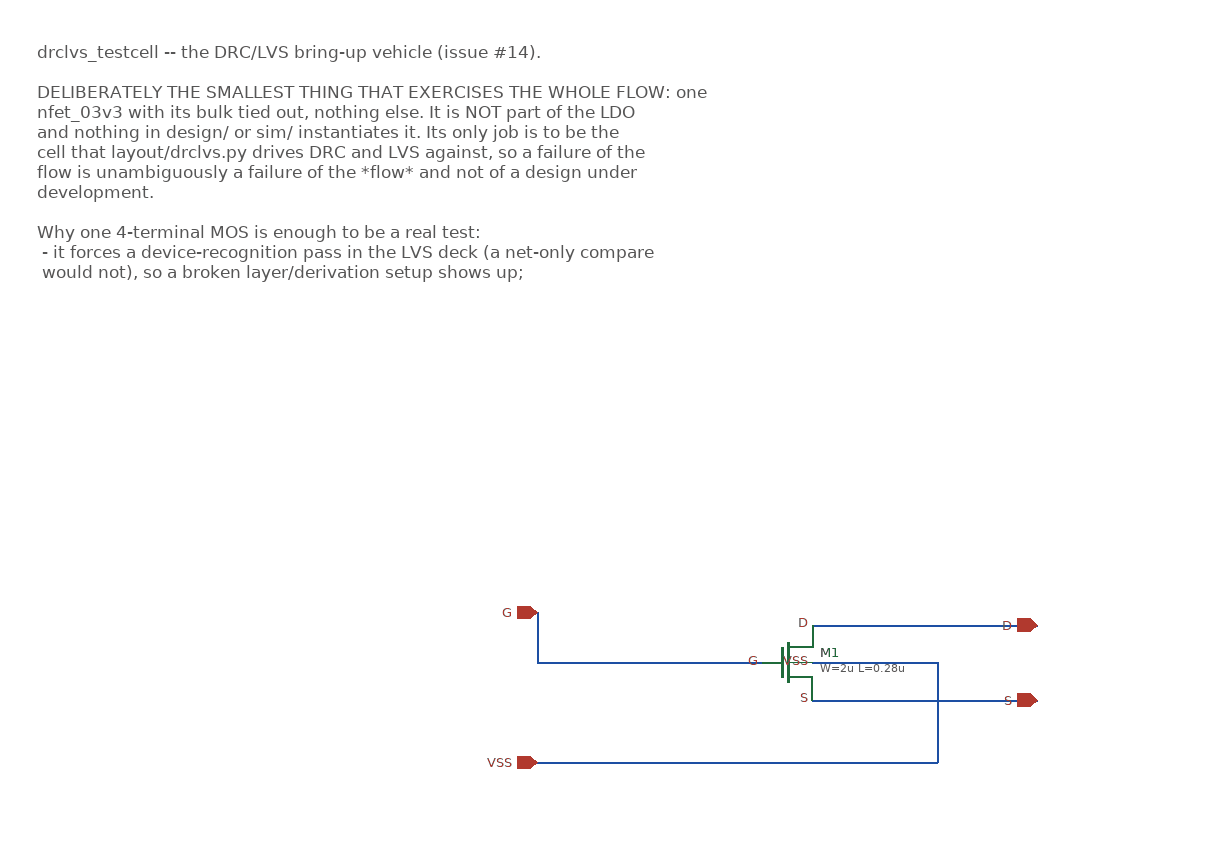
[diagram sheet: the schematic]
v {xschem version=3.4.7 file_version=1.2 }
G {}
K {}
V {}
S {}
E {}
T {drclvs_testcell -- the DRC/LVS bring-up vehicle (issue #14).

DELIBERATELY THE SMALLEST THING THAT EXERCISES THE WHOLE FLOW: one
nfet_03v3 with its bulk tied out, nothing else. It is NOT part of the LDO
and nothing in design/ or sim/ instantiates it. Its only job is to be the
cell that layout/drclvs.py drives DRC and LVS against, so a failure of the
flow is unambiguously a failure of the *flow* and not of a design under
development.

Why one 4-terminal MOS is enough to be a real test:
  - it forces a device-recognition pass in the LVS deck (a net-only compare
    would not), so a broken layer/derivation setup shows up;
  - W, L, nf and m all reach the extracted device, so a parameter-tolerance
    mismatch is detectable;
  - the bulk tie exercises the substrate/global-net path, which is where
    a top-level LVS most often goes wrong first.

PORTS (order is the .subckt port order -- taken from the ipin/opin/iopin
instance order below, since this cell has no symbol):

    D  G  S  VSS

VSS is the device bulk AND the substrate net the pinned LVS deck names itself
(rule_decks/substrate_connections.lvs hardcodes connect_global(..., 'SUB')),
so the guard-ring p-tap in the layout resolves to the same net as the
schematic's bulk terminal. Changing this name means changing it in
layout/drclvs.py too.

The layout counterpart is generated by layout/testcell/gen_gds.py from the
PDK's own nfet PCell -- correct by construction, so a DRC violation points
at the deck/invocation rather than at hand-drawn geometry. Keep W/L/nf/m
here in sync with the PCell parameters there; layout/drclvs.py asserts the
LVS compare passes, which is what catches a drift between the two.} -600 -560 0 0 0.4 0.4 {}
N -200 -100 -200 -60 {lab=G}
N -200 -60 -20 -60 {lab=G}
N 20 -90 200 -90 {lab=D}
N 20 -30 200 -30 {lab=S}
N 20 -60 120 -60 {lab=VSS}
N 120 -60 120 20 {lab=VSS}
N -200 20 120 20 {lab=VSS}
C {symbols/nfet_03v3.sym} 0 -60 0 0 {name=M1 model=nfet_03v3 L=0.28u W=2u nf=1 m=1}
C {devices/lab_pin.sym} 20 -90 0 0 {name=l_d sig_type=std_logic lab=D}
C {devices/lab_pin.sym} -20 -60 0 0 {name=l_g sig_type=std_logic lab=G}
C {devices/lab_pin.sym} 20 -30 0 0 {name=l_s sig_type=std_logic lab=S}
C {devices/lab_pin.sym} 20 -60 0 0 {name=l_b sig_type=std_logic lab=VSS}
C {devices/iopin.sym} 200 -90 0 0 {name=p_d lab=D}
C {devices/ipin.sym} -200 -100 0 0 {name=p_g lab=G}
C {devices/iopin.sym} 200 -30 0 0 {name=p_s lab=S}
C {devices/iopin.sym} -200 20 0 0 {name=p_vss lab=VSS}
